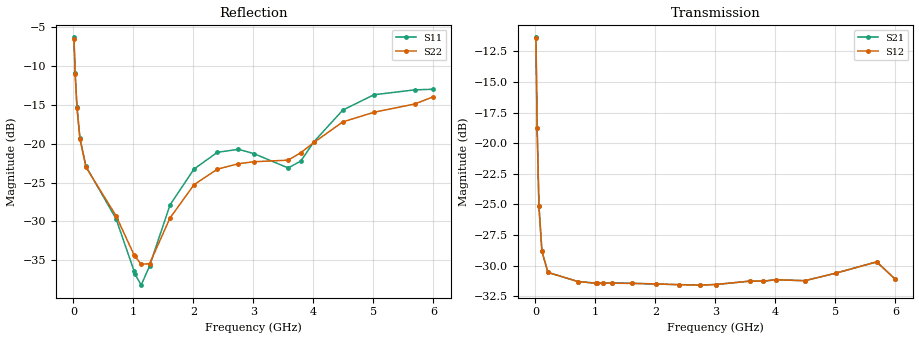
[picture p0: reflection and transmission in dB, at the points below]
! Integrated Device Technology
! Corporate Headquarters
! 6024 Silver Creek Valley Road
! San Jose, CA 95138  USA
! Phone:  1-408-284-8200
! Toll Free:  1-800-223-1366
! Webpage:  http://www.idt.com/
! Timing and RF Division
! 515 Groton Road, Suite 102
! Westford, MA 01886-6024
! Device:  F1951
! Description: 6-bit 0.5 dB Digital Step Attenuator
! Frequency:  100.0 -  4000.00 MHz
! Package:  4x4 mm Thin QFN Plastic Package: 24 pin
! Ports:  2 RF, 6 DC
!  Pin  1  = NC
!  Pin  2  = RF1  =  Port 1
!  Pin  3  = GND
!  Pin  4  = NC
!  Pin  5  = Serial Data Out (SDO)
!  Pin  6  = NC
!  Pin  7  = Reset Bar ( RSTb)
!  Pin  8  = Clock (CLK)
!  Pin  9  = Chip Select Bar (CSb)
!  Pin 10  = NC
!  Pin 11  = Serial Data In (SDI)
!  Pin 12  = NC
!  Pin 13  = NC
!  Pin 14  = VDD
!  Pin 15  = NC
!  Pin 16  = GND
!  Pin 17  = RF2  =  Port 2
!  Pin 18  = NC
!  Pin 19  = GND
!  Pin 20  = GND
!  Pin 21  = GND
!  Pin 22  = GND
!  Pin 23  = GND
!  Pin 24  = GND
! State:  61
! Atten State:  30.5 dB
! Voltage:  +3.30 Volts
! Current:  0.488 mA
! Data:  The device was measured on a F195X evaluation board which has
!  individual transmission lines to the RF pins.  Data was collected
!  de-embedded using a Automatic Fixture Removal [AFR] (Keysight Technologies).
!  The reference plane is the edge of the package pin.
! Misc:  Lot Code  1225BCA
!  Action Tracker AT0399
! Date Measured:  2018-09-13
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# GHz S dB R 50
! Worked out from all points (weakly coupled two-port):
!   600 points, 10 MHz to 6 GHz, reference 50 ohm
!   highest |S21| = -11.36 dB at 10 MHz (marker M1); lowest = -31.6 dB at 2.75 GHz (marker M2)
!   lowest |S11| = -38.2 dB at 1.13 GHz (marker M3), VSWR 1.02, Z = 48.8 + j0.215 ohm
!   |S11| at or under -10 dB: 25.72 MHz to end of sweep
!   |S22| runs from -35.9 to -6.5 dB; largest |S21 - S12| = 0.00021
!   S11 on the Smith chart (normalised r, x): 10 MHz: 1.78, -1.25; 30 MHz: 1.11, -0.62; 60 MHz: 0.98, -0.35; 1.03 GHz: 0.97, -0.01; 6 GHz: 0.81, +0.37
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0.01  -6.30 -33.7  -11.36 -41.5  -11.37 -41.5  -6.52 -33.8
0.03  -10.89 -63.4  -18.78 -67.4  -18.78 -67.5  -11.04 -63.1
0.06  -15.23 -83.3  -25.13 -61.8  -25.14 -61.8  -15.37 -83.2
0.11  -19.31 -101.2  -28.84 -44.1  -28.84 -44.1  -19.39 -101.2
0.21  -22.92 -119.6  -30.55 -27.1  -30.55 -27.0  -23.03 -119.7
0.71  -29.66 -136.5  -31.30 -14.2  -31.30 -14.3  -29.27 -139.0
1.01  -36.35 -158.1  -31.43 -14.5  -31.43 -14.5  -34.31 -153.6
1.03  -36.83 -162.8  -31.44 -14.6  -31.44 -14.5  -34.53 -155.8
1.13  -38.22 169.6  -31.44 -14.7  -31.44 -14.6  -35.53 -170.3
1.27  -35.76 132.4  -31.43 -15.3  -31.43 -15.3  -35.46 164.1
1.61  -27.89 115.6  -31.44 -17.3  -31.45 -17.3  -29.58 135.1
2.01  -23.27 123.1  -31.50 -20.2  -31.49 -20.2  -25.29 135.6
2.4  -21.11 133.3  -31.55 -22.8  -31.56 -22.8  -23.28 140.8
2.75  -20.72 141.8  -31.58 -25.2  -31.59 -25.2  -22.58 145.1
3.01  -21.28 145.7  -31.54 -26.8  -31.54 -26.7  -22.32 145.8
3.58  -23.12 124.6  -31.26 -30.5  -31.26 -30.5  -22.12 129.0
3.79  -22.24 109.0  -31.27 -32.0  -31.27 -31.9  -21.16 122.2
4.01  -19.74 100.6  -31.15 -33.5  -31.15 -33.5  -19.83 116.9
4.49  -15.67 98.9  -31.23 -36.2  -31.23 -36.1  -17.19 114.9
5.01  -13.69 107.6  -30.61 -36.9  -30.61 -36.8  -15.95 117.1
5.69  -13.06 112.4  -29.69 -48.5  -29.69 -48.5  -14.88 109.7
6  -12.98 106.1  -31.12 -47.6  -31.12 -47.6  -13.95 105.7
